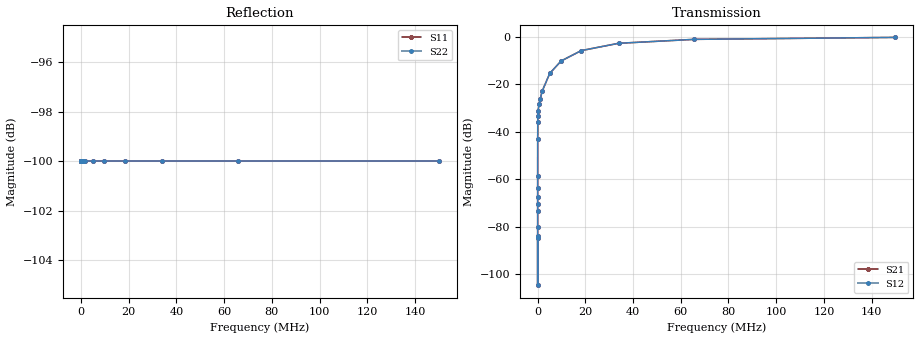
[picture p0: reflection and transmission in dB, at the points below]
! 6/14/2022 3:09 PM
! H:\MS4647B\Production_Data\7041\7041_LF.s2p
! CORRECTED DATA
# Hz S DB R 50.0
! FREQ  S11DB  S11A  S21DB  S21A  S12DB  S12A  S22DB  S22A
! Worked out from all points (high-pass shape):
!   401 points, 10 Hz to 150 MHz, reference 50 ohm
!   highest |S21| = -0.19 dB at 150 MHz (marker M1); lowest = -104.5 dB at 44.24 Hz (marker M2)
!   |S21| within 3 dB of the highest: 30.03 MHz to end of sweep
!   lowest |S11| = -100.0 dB at 10 Hz (marker M3), VSWR 1.00, Z = 50 + j0 ohm
!   |S11| at or under -10 dB: start of sweep to end of sweep
!   |S22| runs from -100.0 to -100.0 dB; largest |S21 - S12| = 0
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10  -100.00 0.0  -83.96 -84.0  -83.96 -84.0  -100.00 0.0
44.24337  -100.00 0.0  -104.54 -104.5  -104.54 -104.5  -100.00 0.0
159.2191  -100.00 0.0  -84.80 -84.8  -84.80 -84.8  -100.00 0.0
250.8059  -100.00 0.0  -79.96 -80.0  -79.96 -80.0  -100.00 0.0
485.7149  -100.00 0.0  -73.47 -73.5  -73.47 -73.5  -100.00 0.0
597.1488  -100.00 0.0  -70.56 -70.6  -70.56 -70.6  -100.00 0.0
980.3143  -100.00 0.0  -67.27 -67.3  -67.27 -67.3  -100.00 0.0
1421.764  -100.00 0.0  -63.72 -63.7  -63.72 -63.7  -100.00 0.0
2535.074  -100.00 0.0  -58.60 -58.6  -58.60 -58.6  -100.00 0.0
15608.48  -100.00 0.0  -43.02 -43.0  -43.02 -43.0  -100.00 0.0
40363.22  -100.00 0.0  -35.80 -35.8  -35.80 -35.8  -100.00 0.0
63581.15  -100.00 0.0  -33.17 -33.2  -33.17 -33.2  -100.00 0.0
104378.5  -100.00 0.0  -31.37 -31.4  -31.37 -31.4  -100.00 0.0
616653.1  -100.00 0.0  -28.19 -28.2  -28.19 -28.2  -100.00 0.0
1055028  -100.00 0.0  -26.23 -26.2  -26.23 -26.2  -100.00 0.0
1881166  -100.00 0.0  -22.84 -22.8  -22.84 -22.8  -100.00 0.0
5069820  -100.00 0.0  -15.35 -15.3  -15.35 -15.3  -100.00 0.0
9818298  -100.00 0.0  -10.14 -10.1  -10.14 -10.1  -100.00 0.0
1.824482e7  -100.00 0.0  -5.77 -5.8  -5.77 -5.8  -100.00 0.0
3.390338e7  -100.00 0.0  -2.68 -2.7  -2.68 -2.7  -100.00 0.0
6.565786e7  -100.00 0.0  -1.02 -1.0  -1.02 -1.0  -100.00 0.0
1.5e8  -100.00 0.0  -0.19 -0.2  -0.19 -0.2  -100.00 0.0
